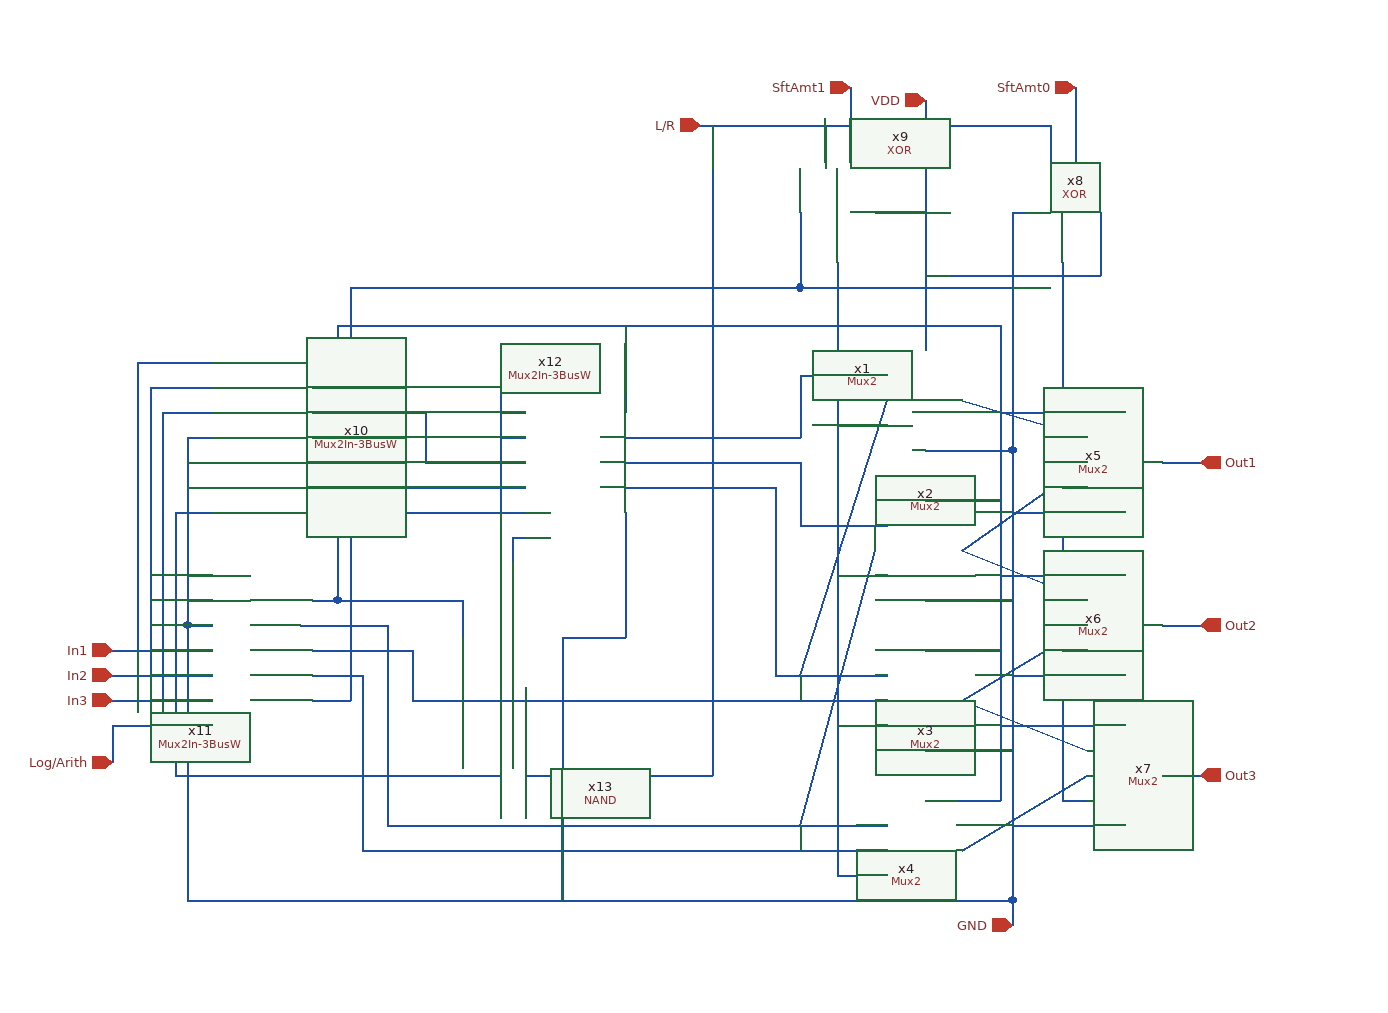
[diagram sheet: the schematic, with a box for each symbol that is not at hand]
v {xschem version=3.4.4 file_version=1.2
}
G {}
K {}
V {}
S {}
E {}
N 70 -80 70 280 {
lab=GND}
N 0 160 70 160 {
lab=GND}
N 0 40 70 40 {
lab=GND}
N 0 -80 70 -80 {
lab=GND}
N 30 -120 130 -90 {
lab=#net1}
N 30 -0 130 40 {
lab=#net2}
N 30 120 130 160 {
lab=#net3}
N 30 240 130 180 {
lab=#net4}
N 30 120 130 60 {
lab=#net3}
N 30 -0 130 -70 {
lab=#net2}
N 110 200 130 200 {
lab=#net5}
N 110 -210 110 200 {
lab=#net5}
N 110 80 130 80 {
lab=#net5}
N 110 -50 130 -50 {
lab=#net5}
N 70 -270 70 -80 {
lab=GND}
N 70 -270 80 -270 {
lab=GND}
N -100 -210 70 -210 {
lab=GND}
N -100 -270 -100 -210 {
lab=GND}
N 110 -230 110 -210 {
lab=#net5}
N -70 -230 -70 260 {
lab=#net6}
N -70 260 -30 260 {
lab=#net6}
N -70 140 -30 140 {
lab=#net6}
N -70 20 -30 20 {
lab=#net6}
N -70 -100 -30 -100 {
lab=#net6}
N 100 -340 100 -310 {
lab=L/R}
N -180 -340 100 -340 {
lab=L/R}
N -80 -340 -80 -310 {
lab=L/R}
N -60 -370 -60 -310 {
lab=SftAmt1}
N 120 -370 120 -310 {
lab=SftAmt0}
N -110 100 -30 100 {
lab=#net7}
N -100 100 -30 -120 {
lab=#net7}
N -0 -360 -0 -160 {
lab=VDD}
N -40 -270 -0 -270 {
lab=VDD}
N -0 -220 140 -220 {
lab=VDD}
N 140 -270 140 -220 {
lab=VDD}
N -0 -180 60 -180 {
lab=VDD}
N 60 -180 60 200 {
lab=VDD}
N -0 200 60 200 {
lab=VDD}
N 0 80 60 80 {
lab=VDD}
N -0 -40 60 -40 {
lab=VDD}
N 70 -30 160 -30 {
lab=GND}
N 70 100 160 100 {
lab=GND}
N 70 220 160 220 {
lab=GND}
N -0 280 70 280 {
lab=GND}
N 70 280 70 300 {
lab=GND}
N 60 20 160 20 {
lab=VDD}
N 60 140 160 140 {
lab=VDD}
N 60 -110 160 -110 {
lab=VDD}
N -210 280 -0 280 {
lab=GND}
N 190 180 220 180 {
lab=Out3}
N 190 60 220 60 {
lab=Out2}
N 190 -70 220 -70 {
lab=Out1}
N -590 -90 -570 -90 {
lab=GND}
N -590 -90 -590 60 {
lab=GND}
N -590 60 -570 60 {
lab=GND}
N -590 40 -570 40 {
lab=GND}
N -590 20 -570 20 {
lab=GND}
N -590 -50 -570 -50 {
lab=GND}
N -590 -70 -570 -70 {
lab=GND}
N -420 280 -210 280 {
lab=GND}
N -590 60 -590 280 {
lab=GND}
N -650 120 -570 120 {
lab=In3}
N -650 100 -570 100 {
lab=In2}
N -650 80 -570 80 {
lab=In1}
N -610 -110 -610 120 {
lab=In3}
N -610 -110 -570 -110 {
lab=In3}
N -620 -130 -620 100 {
lab=In2}
N -620 -130 -570 -130 {
lab=In2}
N -630 -150 -570 -150 {
lab=In1}
N -630 -150 -630 70 {
lab=In1}
N -630 70 -630 80 {
lab=In1}
N -650 140 -650 170 {
lab=Log/Arith}
N -490 -130 -470 -130 {
lab=VDD}
N -470 -130 -470 40 {
lab=VDD}
N -490 40 -470 40 {
lab=VDD}
N -490 -50 -460 -50 {
lab=GND}
N -460 -50 -460 120 {
lab=GND}
N -490 120 -460 120 {
lab=GND}
N -300 -180 -0 -180 {
lab=VDD}
N -470 -180 -470 -130 {
lab=VDD}
N -460 -210 -460 -50 {
lab=GND}
N -290 -210 -100 -210 {
lab=GND}
N -100 -20 -30 -20 {
lab=#net8}
N -100 -140 -30 -140 {
lab=#net9}
N -490 100 -450 100 {
lab=#net10}
N -450 100 -450 240 {
lab=#net10}
N -280 240 -30 240 {
lab=#net10}
N -260 220 -30 220 {
lab=#net11}
N -410 80 -410 120 {
lab=#net12}
N -240 120 -30 120 {
lab=#net12}
N -430 60 -430 220 {
lab=#net11}
N -500 60 -430 60 {
lab=#net11}
N -490 80 -410 80 {
lab=#net12}
N -100 220 -40 0 {
lab=#net11}
N -590 280 -420 280 {
lab=GND}
N -470 -180 -300 -180 {
lab=VDD}
N -460 -210 -290 -210 {
lab=GND}
N -450 240 -280 240 {
lab=#net10}
N -410 120 -240 120 {
lab=#net12}
N -430 220 -260 220 {
lab=#net11}
N -490 -110 -400 -110 {
lab=#net13}
N -400 -110 -400 -70 {
lab=#net13}
N -400 -70 -320 -70 {
lab=#net13}
N -420 -50 -320 -50 {
lab=#net14}
N -420 -90 -420 -50 {
lab=#net14}
N -490 -90 -420 -90 {
lab=#net14}
N -490 -70 -440 -70 {
lab=#net15}
N -440 -70 -440 -30 {
lab=#net15}
N -440 -30 -320 -30 {
lab=#net15}
N -340 -130 -340 -30 {
lab=#net15}
N -340 -130 -320 -130 {
lab=#net15}
N -340 -110 -320 -110 {
lab=#net15}
N -340 -90 -320 -90 {
lab=#net15}
N -650 140 -570 140 {}
N -600 -30 -570 -30 {}
N -600 -30 -600 140 {}
N -600 140 -600 180 {}
N -600 180 -340 180 {}
N -340 110 -340 180 {}
N -170 -340 -170 180 {}
N -320 180 -170 180 {}
N -320 110 -320 180 {}
N -470 40 -370 40 {}
N -370 40 -370 70 {}
N -330 -10 -320 -10 {}
N -330 -10 -330 10 {}
N -290 70 -290 280 {}
N -240 -180 -240 -110 {}
N -240 -30 -240 70 {}
N -290 70 -240 70 {}
N -240 -90 -100 -90 {}
N -100 -140 -100 -90 {}
N -100 -70 -100 -20 {}
N -240 -70 -100 -70 {}
N -240 -50 -120 -50 {}
N -120 -50 -120 100 {}
N -120 100 -110 100 {}
C {workspace/FinalProj/Mux2.sym} 0 -120 0 0 {name=x1}
C {workspace/FinalProj/Mux2.sym} 0 0 0 0 {name=x2}
C {workspace/FinalProj/Mux2.sym} 0 120 0 0 {name=x3}
C {workspace/FinalProj/Mux2.sym} 0 240 0 0 {name=x4}
C {workspace/FinalProj/Mux2.sym} 160 -70 0 0 {name=x5}
C {workspace/FinalProj/Mux2.sym} 160 60 0 0 {name=x6}
C {workspace/FinalProj/Mux2.sym} 160 180 0 0 {name=x7}
C {iopin.sym} 70 300 1 0 {name=GND lab=GND}
C {workspace/FinalProj/XOR.sym} 110 -260 1 0 {name=x8}
C {workspace/FinalProj/XOR.sym} -70 -260 1 0 {name=x9}
C {ipin.sym} -650 80 0 0 {name=In1 lab=In1}
C {ipin.sym} -650 100 0 0 {name=In2 lab=In2}
C {ipin.sym} -650 120 0 0 {name=In3 lab=In3}
C {iopin.sym} 0 -360 3 0 {name=VDD lab=VDD}
C {opin.sym} 220 -70 0 0 {name=Out1 lab=Out1}
C {opin.sym} 220 60 0 0 {name=Out2 lab=Out2}
C {opin.sym} 220 180 0 0 {name=Out3 lab=Out3}
C {ipin.sym} 120 -370 1 0 {name=SftAmt0 lab=SftAmt0}
C {ipin.sym} -60 -370 1 0 {name=SftAmt1 lab=SftAmt1}
C {ipin.sym} -180 -340 0 0 {name=L/R lab=L/R}
C {workspace/FinalProj/Mux2In-3BusW.sym} -420 -90 0 0 {name=x10}
C {workspace/FinalProj/Mux2In-3BusW.sym} -420 80 0 0 {name=x11}
C {ipin.sym} -650 170 3 0 {name=Log/Arith lab=Log/Arith}
C {workspace/FinalProj/Mux2In-3BusW.sym} -170 -70 0 0 {name=x12}
C {workspace/FinalProj/NAND.sym} -330 60 3 0 {name=x13}
